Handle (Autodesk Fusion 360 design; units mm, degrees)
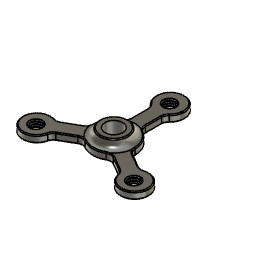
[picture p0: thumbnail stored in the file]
derived_base_feature "Derived Base Feature" bodies "Handle"
named bodies: "Handle"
